VERSION 5.7 ;
  NOWIREEXTENSIONATPIN ON ;
  DIVIDERCHAR "/" ;
  BUSBITCHARS "[]" ;
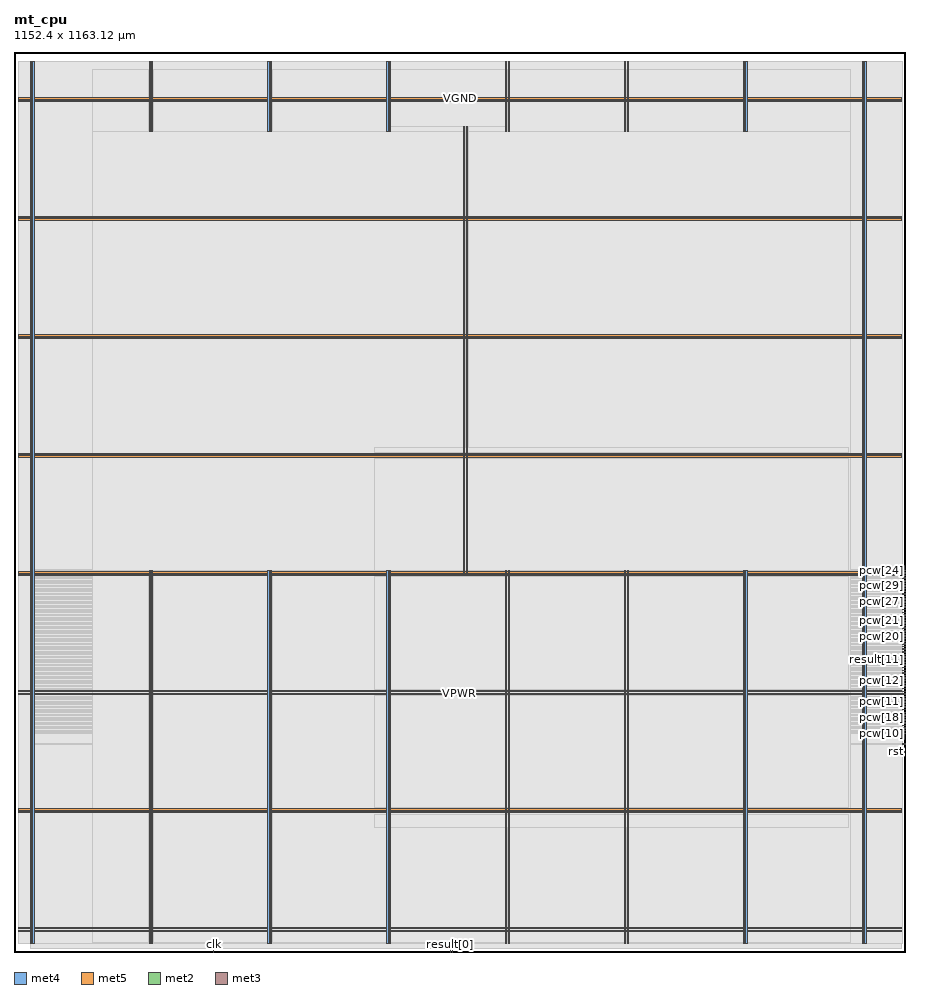
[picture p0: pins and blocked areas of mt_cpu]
MACRO mt_cpu
  CLASS BLOCK ;
  FOREIGN mt_cpu ;
  ORIGIN 0.000 0.000 ;
  SIZE 1152.405 BY 1163.125 ;
  PIN VGND
    DIRECTION INOUT ;
    USE GROUND ;
    PORT
      LAYER met4 ;
        RECT 24.340 10.640 25.940 1150.800 ;
    END
    PORT
      LAYER met4 ;
        RECT 177.940 10.640 179.540 492.595 ;
    END
    PORT
      LAYER met4 ;
        RECT 177.940 1060.925 179.540 1150.800 ;
    END
    PORT
      LAYER met4 ;
        RECT 331.540 10.640 333.140 492.595 ;
    END
    PORT
      LAYER met4 ;
        RECT 331.540 1060.925 333.140 1150.800 ;
    END
    PORT
      LAYER met4 ;
        RECT 485.140 10.640 486.740 492.595 ;
    END
    PORT
      LAYER met4 ;
        RECT 485.140 1060.925 486.740 1150.800 ;
    END
    PORT
      LAYER met4 ;
        RECT 638.740 10.640 640.340 492.595 ;
    END
    PORT
      LAYER met4 ;
        RECT 638.740 1060.925 640.340 1150.800 ;
    END
    PORT
      LAYER met4 ;
        RECT 792.340 10.640 793.940 492.595 ;
    END
    PORT
      LAYER met4 ;
        RECT 792.340 1060.925 793.940 1150.800 ;
    END
    PORT
      LAYER met4 ;
        RECT 945.940 10.640 947.540 492.595 ;
    END
    PORT
      LAYER met4 ;
        RECT 945.940 1060.925 947.540 1150.800 ;
    END
    PORT
      LAYER met4 ;
        RECT 1099.540 10.640 1101.140 1150.800 ;
    END
    PORT
      LAYER met5 ;
        RECT 5.280 30.030 1147.020 31.630 ;
    END
    PORT
      LAYER met5 ;
        RECT 5.280 183.210 1147.020 184.810 ;
    END
    PORT
      LAYER met5 ;
        RECT 5.280 336.390 1147.020 337.990 ;
    END
    PORT
      LAYER met5 ;
        RECT 5.280 489.570 1147.020 491.170 ;
    END
    PORT
      LAYER met5 ;
        RECT 5.280 642.750 1147.020 644.350 ;
    END
    PORT
      LAYER met5 ;
        RECT 5.280 795.930 1147.020 797.530 ;
    END
    PORT
      LAYER met5 ;
        RECT 5.280 949.110 1147.020 950.710 ;
    END
    PORT
      LAYER met5 ;
        RECT 5.280 1102.290 1147.020 1103.890 ;
    END
    PORT
      LAYER met4 ;
        RECT 584.780 486.640 586.380 1066.480 ;
    END
  END VGND
  PIN VPWR
    DIRECTION INOUT ;
    USE POWER ;
    PORT
      LAYER met4 ;
        RECT 21.040 10.640 22.640 1150.800 ;
    END
    PORT
      LAYER met4 ;
        RECT 174.640 10.640 176.240 492.595 ;
    END
    PORT
      LAYER met4 ;
        RECT 174.640 1060.925 176.240 1150.800 ;
    END
    PORT
      LAYER met4 ;
        RECT 328.240 10.640 329.840 492.595 ;
    END
    PORT
      LAYER met4 ;
        RECT 328.240 1060.925 329.840 1150.800 ;
    END
    PORT
      LAYER met4 ;
        RECT 481.840 10.640 483.440 492.595 ;
    END
    PORT
      LAYER met4 ;
        RECT 481.840 1060.925 483.440 1150.800 ;
    END
    PORT
      LAYER met4 ;
        RECT 635.440 10.640 637.040 492.595 ;
    END
    PORT
      LAYER met4 ;
        RECT 635.440 1060.925 637.040 1150.800 ;
    END
    PORT
      LAYER met4 ;
        RECT 789.040 10.640 790.640 492.595 ;
    END
    PORT
      LAYER met4 ;
        RECT 789.040 1060.925 790.640 1150.800 ;
    END
    PORT
      LAYER met4 ;
        RECT 942.640 10.640 944.240 492.595 ;
    END
    PORT
      LAYER met4 ;
        RECT 942.640 1060.925 944.240 1150.800 ;
    END
    PORT
      LAYER met4 ;
        RECT 1096.240 10.640 1097.840 1150.800 ;
    END
    PORT
      LAYER met5 ;
        RECT 5.280 26.730 1147.020 28.330 ;
    END
    PORT
      LAYER met5 ;
        RECT 5.280 179.910 1147.020 181.510 ;
    END
    PORT
      LAYER met5 ;
        RECT 5.280 333.090 1147.020 334.690 ;
    END
    PORT
      LAYER met5 ;
        RECT 5.280 486.270 1147.020 487.870 ;
    END
    PORT
      LAYER met5 ;
        RECT 5.280 639.450 1147.020 641.050 ;
    END
    PORT
      LAYER met5 ;
        RECT 5.280 792.630 1147.020 794.230 ;
    END
    PORT
      LAYER met5 ;
        RECT 5.280 945.810 1147.020 947.410 ;
    END
    PORT
      LAYER met5 ;
        RECT 5.280 1098.990 1147.020 1100.590 ;
    END
    PORT
      LAYER met4 ;
        RECT 581.100 486.640 582.700 1066.480 ;
    END
  END VPWR
  PIN clk
    DIRECTION INPUT ;
    USE SIGNAL ;
    ANTENNAGATEAREA 2.573400 ;
    ANTENNADIFFAREA 0.869400 ;
    PORT
      LAYER met2 ;
        RECT 257.690 0.000 257.970 4.000 ;
    END
  END clk
  PIN pcw[0]
    DIRECTION OUTPUT ;
    USE SIGNAL ;
    ANTENNADIFFAREA 0.340600 ;
    PORT
      LAYER met3 ;
        RECT 1148.405 387.640 1152.405 388.240 ;
    END
  END pcw[0]
  PIN pcw[10]
    DIRECTION OUTPUT ;
    USE SIGNAL ;
    ANTENNADIFFAREA 0.340600 ;
    PORT
      LAYER met3 ;
        RECT 1148.405 282.240 1152.405 282.840 ;
    END
  END pcw[10]
  PIN pcw[11]
    DIRECTION OUTPUT ;
    USE SIGNAL ;
    ANTENNADIFFAREA 0.340600 ;
    PORT
      LAYER met3 ;
        RECT 1148.405 323.040 1152.405 323.640 ;
    END
  END pcw[11]
  PIN pcw[12]
    DIRECTION OUTPUT ;
    USE SIGNAL ;
    ANTENNADIFFAREA 0.340600 ;
    PORT
      LAYER met3 ;
        RECT 1148.405 340.040 1152.405 340.640 ;
    END
  END pcw[12]
  PIN pcw[13]
    DIRECTION OUTPUT ;
    USE SIGNAL ;
    ANTENNADIFFAREA 0.340600 ;
    PORT
      LAYER met3 ;
        RECT 1148.405 326.440 1152.405 327.040 ;
    END
  END pcw[13]
  PIN pcw[14]
    DIRECTION OUTPUT ;
    USE SIGNAL ;
    ANTENNADIFFAREA 0.340600 ;
    PORT
      LAYER met3 ;
        RECT 1148.405 329.840 1152.405 330.440 ;
    END
  END pcw[14]
  PIN pcw[15]
    DIRECTION OUTPUT ;
    USE SIGNAL ;
    ANTENNADIFFAREA 0.340600 ;
    PORT
      LAYER met3 ;
        RECT 1148.405 333.240 1152.405 333.840 ;
    END
  END pcw[15]
  PIN pcw[16]
    DIRECTION OUTPUT ;
    USE SIGNAL ;
    ANTENNADIFFAREA 0.340600 ;
    PORT
      LAYER met3 ;
        RECT 1148.405 336.640 1152.405 337.240 ;
    END
  END pcw[16]
  PIN pcw[17]
    DIRECTION OUTPUT ;
    USE SIGNAL ;
    ANTENNADIFFAREA 0.340600 ;
    PORT
      LAYER met3 ;
        RECT 1148.405 306.040 1152.405 306.640 ;
    END
  END pcw[17]
  PIN pcw[18]
    DIRECTION OUTPUT ;
    USE SIGNAL ;
    ANTENNADIFFAREA 0.340600 ;
    PORT
      LAYER met3 ;
        RECT 1148.405 292.440 1152.405 293.040 ;
    END
  END pcw[18]
  PIN pcw[19]
    DIRECTION OUTPUT ;
    USE SIGNAL ;
    ANTENNADIFFAREA 0.340600 ;
    PORT
      LAYER met3 ;
        RECT 1148.405 380.840 1152.405 381.440 ;
    END
  END pcw[19]
  PIN pcw[1]
    DIRECTION OUTPUT ;
    USE SIGNAL ;
    ANTENNADIFFAREA 0.340600 ;
    PORT
      LAYER met3 ;
        RECT 1148.405 397.840 1152.405 398.440 ;
    END
  END pcw[1]
  PIN pcw[20]
    DIRECTION OUTPUT ;
    USE SIGNAL ;
    ANTENNADIFFAREA 0.340600 ;
    PORT
      LAYER met3 ;
        RECT 1148.405 408.040 1152.405 408.640 ;
    END
  END pcw[20]
  PIN pcw[21]
    DIRECTION OUTPUT ;
    USE SIGNAL ;
    ANTENNADIFFAREA 0.340600 ;
    PORT
      LAYER met3 ;
        RECT 1148.405 418.240 1152.405 418.840 ;
    END
  END pcw[21]
  PIN pcw[22]
    DIRECTION OUTPUT ;
    USE SIGNAL ;
    ANTENNADIFFAREA 0.340600 ;
    PORT
      LAYER met3 ;
        RECT 1148.405 421.640 1152.405 422.240 ;
    END
  END pcw[22]
  PIN pcw[23]
    DIRECTION OUTPUT ;
    USE SIGNAL ;
    ANTENNADIFFAREA 0.340600 ;
    PORT
      LAYER met3 ;
        RECT 1148.405 428.440 1152.405 429.040 ;
    END
  END pcw[23]
  PIN pcw[24]
    DIRECTION OUTPUT ;
    USE SIGNAL ;
    ANTENNADIFFAREA 0.340600 ;
    PORT
      LAYER met3 ;
        RECT 1148.405 493.040 1152.405 493.640 ;
    END
  END pcw[24]
  PIN pcw[25]
    DIRECTION OUTPUT ;
    USE SIGNAL ;
    ANTENNADIFFAREA 0.340600 ;
    PORT
      LAYER met3 ;
        RECT 1148.405 489.640 1152.405 490.240 ;
    END
  END pcw[25]
  PIN pcw[26]
    DIRECTION OUTPUT ;
    USE SIGNAL ;
    ANTENNADIFFAREA 0.340600 ;
    PORT
      LAYER met3 ;
        RECT 1148.405 486.240 1152.405 486.840 ;
    END
  END pcw[26]
  PIN pcw[27]
    DIRECTION OUTPUT ;
    USE SIGNAL ;
    ANTENNADIFFAREA 0.340600 ;
    PORT
      LAYER met3 ;
        RECT 1148.405 442.040 1152.405 442.640 ;
    END
  END pcw[27]
  PIN pcw[28]
    DIRECTION OUTPUT ;
    USE SIGNAL ;
    ANTENNADIFFAREA 0.340600 ;
    PORT
      LAYER met3 ;
        RECT 1148.405 445.440 1152.405 446.040 ;
    END
  END pcw[28]
  PIN pcw[29]
    DIRECTION OUTPUT ;
    USE SIGNAL ;
    ANTENNADIFFAREA 0.340600 ;
    PORT
      LAYER met3 ;
        RECT 1148.405 482.840 1152.405 483.440 ;
    END
  END pcw[29]
  PIN pcw[2]
    DIRECTION OUTPUT ;
    USE SIGNAL ;
    ANTENNADIFFAREA 0.340600 ;
    PORT
      LAYER met2 ;
        RECT 566.810 0.000 567.090 4.000 ;
    END
  END pcw[2]
  PIN pcw[30]
    DIRECTION OUTPUT ;
    USE SIGNAL ;
    ANTENNADIFFAREA 0.340600 ;
    PORT
      LAYER met3 ;
        RECT 1148.405 459.040 1152.405 459.640 ;
    END
  END pcw[30]
  PIN pcw[31]
    DIRECTION OUTPUT ;
    USE SIGNAL ;
    ANTENNADIFFAREA 0.340600 ;
    PORT
      LAYER met3 ;
        RECT 1148.405 452.240 1152.405 452.840 ;
    END
  END pcw[31]
  PIN pcw[3]
    DIRECTION OUTPUT ;
    USE SIGNAL ;
    ANTENNADIFFAREA 0.340600 ;
    PORT
      LAYER met3 ;
        RECT 1148.405 285.640 1152.405 286.240 ;
    END
  END pcw[3]
  PIN pcw[4]
    DIRECTION OUTPUT ;
    USE SIGNAL ;
    ANTENNADIFFAREA 0.340600 ;
    PORT
      LAYER met3 ;
        RECT 1148.405 360.440 1152.405 361.040 ;
    END
  END pcw[4]
  PIN pcw[5]
    DIRECTION OUTPUT ;
    USE SIGNAL ;
    ANTENNADIFFAREA 0.340600 ;
    PORT
      LAYER met3 ;
        RECT 1148.405 295.840 1152.405 296.440 ;
    END
  END pcw[5]
  PIN pcw[6]
    DIRECTION OUTPUT ;
    USE SIGNAL ;
    ANTENNADIFFAREA 0.340600 ;
    PORT
      LAYER met3 ;
        RECT 1148.405 302.640 1152.405 303.240 ;
    END
  END pcw[6]
  PIN pcw[7]
    DIRECTION OUTPUT ;
    USE SIGNAL ;
    ANTENNADIFFAREA 0.340600 ;
    PORT
      LAYER met3 ;
        RECT 1148.405 350.240 1152.405 350.840 ;
    END
  END pcw[7]
  PIN pcw[8]
    DIRECTION OUTPUT ;
    USE SIGNAL ;
    ANTENNADIFFAREA 0.340600 ;
    PORT
      LAYER met3 ;
        RECT 1148.405 309.440 1152.405 310.040 ;
    END
  END pcw[8]
  PIN pcw[9]
    DIRECTION OUTPUT ;
    USE SIGNAL ;
    ANTENNADIFFAREA 0.340600 ;
    PORT
      LAYER met3 ;
        RECT 1148.405 319.640 1152.405 320.240 ;
    END
  END pcw[9]
  PIN result[0]
    DIRECTION OUTPUT ;
    USE SIGNAL ;
    ANTENNADIFFAREA 0.340600 ;
    PORT
      LAYER met2 ;
        RECT 563.590 0.000 563.870 4.000 ;
    END
  END result[0]
  PIN result[10]
    DIRECTION OUTPUT ;
    USE SIGNAL ;
    ANTENNADIFFAREA 0.340600 ;
    PORT
      LAYER met3 ;
        RECT 1148.405 377.440 1152.405 378.040 ;
    END
  END result[10]
  PIN result[11]
    DIRECTION OUTPUT ;
    USE SIGNAL ;
    ANTENNADIFFAREA 0.340600 ;
    PORT
      LAYER met3 ;
        RECT 1148.405 367.240 1152.405 367.840 ;
    END
  END result[11]
  PIN result[12]
    DIRECTION OUTPUT ;
    USE SIGNAL ;
    ANTENNADIFFAREA 0.340600 ;
    PORT
      LAYER met3 ;
        RECT 1148.405 357.040 1152.405 357.640 ;
    END
  END result[12]
  PIN result[13]
    DIRECTION OUTPUT ;
    USE SIGNAL ;
    ANTENNADIFFAREA 0.340600 ;
    PORT
      LAYER met3 ;
        RECT 1148.405 299.240 1152.405 299.840 ;
    END
  END result[13]
  PIN result[14]
    DIRECTION OUTPUT ;
    USE SIGNAL ;
    ANTENNADIFFAREA 0.340600 ;
    PORT
      LAYER met3 ;
        RECT 1148.405 312.840 1152.405 313.440 ;
    END
  END result[14]
  PIN result[15]
    DIRECTION OUTPUT ;
    USE SIGNAL ;
    ANTENNADIFFAREA 0.340600 ;
    PORT
      LAYER met3 ;
        RECT 1148.405 343.440 1152.405 344.040 ;
    END
  END result[15]
  PIN result[16]
    DIRECTION OUTPUT ;
    USE SIGNAL ;
    ANTENNADIFFAREA 0.340600 ;
    PORT
      LAYER met3 ;
        RECT 1148.405 346.840 1152.405 347.440 ;
    END
  END result[16]
  PIN result[17]
    DIRECTION OUTPUT ;
    USE SIGNAL ;
    ANTENNADIFFAREA 0.340600 ;
    PORT
      LAYER met3 ;
        RECT 1148.405 289.040 1152.405 289.640 ;
    END
  END result[17]
  PIN result[18]
    DIRECTION OUTPUT ;
    USE SIGNAL ;
    ANTENNADIFFAREA 0.340600 ;
    PORT
      LAYER met3 ;
        RECT 1148.405 370.640 1152.405 371.240 ;
    END
  END result[18]
  PIN result[19]
    DIRECTION OUTPUT ;
    USE SIGNAL ;
    ANTENNADIFFAREA 0.340600 ;
    PORT
      LAYER met3 ;
        RECT 1148.405 404.640 1152.405 405.240 ;
    END
  END result[19]
  PIN result[1]
    DIRECTION OUTPUT ;
    USE SIGNAL ;
    ANTENNADIFFAREA 0.340600 ;
    PORT
      LAYER met3 ;
        RECT 1148.405 401.240 1152.405 401.840 ;
    END
  END result[1]
  PIN result[20]
    DIRECTION OUTPUT ;
    USE SIGNAL ;
    ANTENNADIFFAREA 0.340600 ;
    PORT
      LAYER met3 ;
        RECT 1148.405 431.840 1152.405 432.440 ;
    END
  END result[20]
  PIN result[21]
    DIRECTION OUTPUT ;
    USE SIGNAL ;
    ANTENNADIFFAREA 0.340600 ;
    PORT
      LAYER met3 ;
        RECT 1148.405 462.440 1152.405 463.040 ;
    END
  END result[21]
  PIN result[22]
    DIRECTION OUTPUT ;
    USE SIGNAL ;
    ANTENNADIFFAREA 0.340600 ;
    PORT
      LAYER met3 ;
        RECT 1148.405 425.040 1152.405 425.640 ;
    END
  END result[22]
  PIN result[23]
    DIRECTION OUTPUT ;
    USE SIGNAL ;
    ANTENNADIFFAREA 0.340600 ;
    PORT
      LAYER met3 ;
        RECT 1148.405 448.840 1152.405 449.440 ;
    END
  END result[23]
  PIN result[24]
    DIRECTION OUTPUT ;
    USE SIGNAL ;
    ANTENNADIFFAREA 0.340600 ;
    PORT
      LAYER met3 ;
        RECT 1148.405 465.840 1152.405 466.440 ;
    END
  END result[24]
  PIN result[25]
    DIRECTION OUTPUT ;
    USE SIGNAL ;
    ANTENNADIFFAREA 0.340600 ;
    PORT
      LAYER met3 ;
        RECT 1148.405 438.640 1152.405 439.240 ;
    END
  END result[25]
  PIN result[26]
    DIRECTION OUTPUT ;
    USE SIGNAL ;
    ANTENNADIFFAREA 0.340600 ;
    PORT
      LAYER met3 ;
        RECT 1148.405 435.240 1152.405 435.840 ;
    END
  END result[26]
  PIN result[27]
    DIRECTION OUTPUT ;
    USE SIGNAL ;
    ANTENNADIFFAREA 0.340600 ;
    PORT
      LAYER met3 ;
        RECT 1148.405 479.440 1152.405 480.040 ;
    END
  END result[27]
  PIN result[28]
    DIRECTION OUTPUT ;
    USE SIGNAL ;
    ANTENNADIFFAREA 0.340600 ;
    PORT
      LAYER met3 ;
        RECT 1148.405 476.040 1152.405 476.640 ;
    END
  END result[28]
  PIN result[29]
    DIRECTION OUTPUT ;
    USE SIGNAL ;
    ANTENNADIFFAREA 0.340600 ;
    PORT
      LAYER met3 ;
        RECT 1148.405 455.640 1152.405 456.240 ;
    END
  END result[29]
  PIN result[2]
    DIRECTION OUTPUT ;
    USE SIGNAL ;
    ANTENNADIFFAREA 0.340600 ;
    PORT
      LAYER met3 ;
        RECT 1148.405 384.240 1152.405 384.840 ;
    END
  END result[2]
  PIN result[30]
    DIRECTION OUTPUT ;
    USE SIGNAL ;
    ANTENNADIFFAREA 0.340600 ;
    PORT
      LAYER met3 ;
        RECT 1148.405 469.240 1152.405 469.840 ;
    END
  END result[30]
  PIN result[31]
    DIRECTION OUTPUT ;
    USE SIGNAL ;
    ANTENNADIFFAREA 0.340600 ;
    PORT
      LAYER met3 ;
        RECT 1148.405 472.640 1152.405 473.240 ;
    END
  END result[31]
  PIN result[3]
    DIRECTION OUTPUT ;
    USE SIGNAL ;
    ANTENNADIFFAREA 0.340600 ;
    PORT
      LAYER met3 ;
        RECT 1148.405 414.840 1152.405 415.440 ;
    END
  END result[3]
  PIN result[4]
    DIRECTION OUTPUT ;
    USE SIGNAL ;
    ANTENNADIFFAREA 0.340600 ;
    PORT
      LAYER met3 ;
        RECT 1148.405 411.440 1152.405 412.040 ;
    END
  END result[4]
  PIN result[5]
    DIRECTION OUTPUT ;
    USE SIGNAL ;
    ANTENNADIFFAREA 0.340600 ;
    PORT
      LAYER met3 ;
        RECT 1148.405 374.040 1152.405 374.640 ;
    END
  END result[5]
  PIN result[6]
    DIRECTION OUTPUT ;
    USE SIGNAL ;
    ANTENNADIFFAREA 0.340600 ;
    PORT
      LAYER met3 ;
        RECT 1148.405 363.840 1152.405 364.440 ;
    END
  END result[6]
  PIN result[7]
    DIRECTION OUTPUT ;
    USE SIGNAL ;
    ANTENNADIFFAREA 0.340600 ;
    PORT
      LAYER met3 ;
        RECT 1148.405 394.440 1152.405 395.040 ;
    END
  END result[7]
  PIN result[8]
    DIRECTION OUTPUT ;
    USE SIGNAL ;
    ANTENNADIFFAREA 0.340600 ;
    PORT
      LAYER met3 ;
        RECT 1148.405 391.040 1152.405 391.640 ;
    END
  END result[8]
  PIN result[9]
    DIRECTION OUTPUT ;
    USE SIGNAL ;
    ANTENNADIFFAREA 0.340600 ;
    PORT
      LAYER met3 ;
        RECT 1148.405 353.640 1152.405 354.240 ;
    END
  END result[9]
  PIN rst
    DIRECTION INPUT ;
    USE SIGNAL ;
    ANTENNAGATEAREA 0.929700 ;
    ANTENNADIFFAREA 0.434700 ;
    PORT
      LAYER met3 ;
        RECT 1148.405 268.640 1152.405 269.240 ;
    END
  END rst
  PIN swap_tgrp
    DIRECTION INPUT ;
    USE SIGNAL ;
    ANTENNAGATEAREA 0.682200 ;
    ANTENNADIFFAREA 0.434700 ;
    PORT
      LAYER met3 ;
        RECT 1148.405 316.240 1152.405 316.840 ;
    END
  END swap_tgrp
  OBS
      LAYER nwell ;
        RECT 5.330 10.795 1146.970 1150.750 ;
      LAYER li1 ;
        RECT 5.520 10.795 1146.780 1150.645 ;
      LAYER met1 ;
        RECT 5.520 10.640 1147.170 1150.800 ;
      LAYER met2 ;
        RECT 21.070 4.280 1147.150 1150.745 ;
        RECT 21.070 4.000 257.410 4.280 ;
        RECT 258.250 4.000 563.310 4.280 ;
        RECT 564.150 4.000 566.530 4.280 ;
        RECT 567.370 4.000 1147.150 4.280 ;
      LAYER met3 ;
        RECT 21.050 494.040 1148.405 1150.725 ;
        RECT 21.050 492.640 1148.005 494.040 ;
        RECT 21.050 490.640 1148.405 492.640 ;
        RECT 21.050 489.240 1148.005 490.640 ;
        RECT 21.050 487.240 1148.405 489.240 ;
        RECT 21.050 485.840 1148.005 487.240 ;
        RECT 21.050 483.840 1148.405 485.840 ;
        RECT 21.050 482.440 1148.005 483.840 ;
        RECT 21.050 480.440 1148.405 482.440 ;
        RECT 21.050 479.040 1148.005 480.440 ;
        RECT 21.050 477.040 1148.405 479.040 ;
        RECT 21.050 475.640 1148.005 477.040 ;
        RECT 21.050 473.640 1148.405 475.640 ;
        RECT 21.050 472.240 1148.005 473.640 ;
        RECT 21.050 470.240 1148.405 472.240 ;
        RECT 21.050 468.840 1148.005 470.240 ;
        RECT 21.050 466.840 1148.405 468.840 ;
        RECT 21.050 465.440 1148.005 466.840 ;
        RECT 21.050 463.440 1148.405 465.440 ;
        RECT 21.050 462.040 1148.005 463.440 ;
        RECT 21.050 460.040 1148.405 462.040 ;
        RECT 21.050 458.640 1148.005 460.040 ;
        RECT 21.050 456.640 1148.405 458.640 ;
        RECT 21.050 455.240 1148.005 456.640 ;
        RECT 21.050 453.240 1148.405 455.240 ;
        RECT 21.050 451.840 1148.005 453.240 ;
        RECT 21.050 449.840 1148.405 451.840 ;
        RECT 21.050 448.440 1148.005 449.840 ;
        RECT 21.050 446.440 1148.405 448.440 ;
        RECT 21.050 445.040 1148.005 446.440 ;
        RECT 21.050 443.040 1148.405 445.040 ;
        RECT 21.050 441.640 1148.005 443.040 ;
        RECT 21.050 439.640 1148.405 441.640 ;
        RECT 21.050 438.240 1148.005 439.640 ;
        RECT 21.050 436.240 1148.405 438.240 ;
        RECT 21.050 434.840 1148.005 436.240 ;
        RECT 21.050 432.840 1148.405 434.840 ;
        RECT 21.050 431.440 1148.005 432.840 ;
        RECT 21.050 429.440 1148.405 431.440 ;
        RECT 21.050 428.040 1148.005 429.440 ;
        RECT 21.050 426.040 1148.405 428.040 ;
        RECT 21.050 424.640 1148.005 426.040 ;
        RECT 21.050 422.640 1148.405 424.640 ;
        RECT 21.050 421.240 1148.005 422.640 ;
        RECT 21.050 419.240 1148.405 421.240 ;
        RECT 21.050 417.840 1148.005 419.240 ;
        RECT 21.050 415.840 1148.405 417.840 ;
        RECT 21.050 414.440 1148.005 415.840 ;
        RECT 21.050 412.440 1148.405 414.440 ;
        RECT 21.050 411.040 1148.005 412.440 ;
        RECT 21.050 409.040 1148.405 411.040 ;
        RECT 21.050 407.640 1148.005 409.040 ;
        RECT 21.050 405.640 1148.405 407.640 ;
        RECT 21.050 404.240 1148.005 405.640 ;
        RECT 21.050 402.240 1148.405 404.240 ;
        RECT 21.050 400.840 1148.005 402.240 ;
        RECT 21.050 398.840 1148.405 400.840 ;
        RECT 21.050 397.440 1148.005 398.840 ;
        RECT 21.050 395.440 1148.405 397.440 ;
        RECT 21.050 394.040 1148.005 395.440 ;
        RECT 21.050 392.040 1148.405 394.040 ;
        RECT 21.050 390.640 1148.005 392.040 ;
        RECT 21.050 388.640 1148.405 390.640 ;
        RECT 21.050 387.240 1148.005 388.640 ;
        RECT 21.050 385.240 1148.405 387.240 ;
        RECT 21.050 383.840 1148.005 385.240 ;
        RECT 21.050 381.840 1148.405 383.840 ;
        RECT 21.050 380.440 1148.005 381.840 ;
        RECT 21.050 378.440 1148.405 380.440 ;
        RECT 21.050 377.040 1148.005 378.440 ;
        RECT 21.050 375.040 1148.405 377.040 ;
        RECT 21.050 373.640 1148.005 375.040 ;
        RECT 21.050 371.640 1148.405 373.640 ;
        RECT 21.050 370.240 1148.005 371.640 ;
        RECT 21.050 368.240 1148.405 370.240 ;
        RECT 21.050 366.840 1148.005 368.240 ;
        RECT 21.050 364.840 1148.405 366.840 ;
        RECT 21.050 363.440 1148.005 364.840 ;
        RECT 21.050 361.440 1148.405 363.440 ;
        RECT 21.050 360.040 1148.005 361.440 ;
        RECT 21.050 358.040 1148.405 360.040 ;
        RECT 21.050 356.640 1148.005 358.040 ;
        RECT 21.050 354.640 1148.405 356.640 ;
        RECT 21.050 353.240 1148.005 354.640 ;
        RECT 21.050 351.240 1148.405 353.240 ;
        RECT 21.050 349.840 1148.005 351.240 ;
        RECT 21.050 347.840 1148.405 349.840 ;
        RECT 21.050 346.440 1148.005 347.840 ;
        RECT 21.050 344.440 1148.405 346.440 ;
        RECT 21.050 343.040 1148.005 344.440 ;
        RECT 21.050 341.040 1148.405 343.040 ;
        RECT 21.050 339.640 1148.005 341.040 ;
        RECT 21.050 337.640 1148.405 339.640 ;
        RECT 21.050 336.240 1148.005 337.640 ;
        RECT 21.050 334.240 1148.405 336.240 ;
        RECT 21.050 332.840 1148.005 334.240 ;
        RECT 21.050 330.840 1148.405 332.840 ;
        RECT 21.050 329.440 1148.005 330.840 ;
        RECT 21.050 327.440 1148.405 329.440 ;
        RECT 21.050 326.040 1148.005 327.440 ;
        RECT 21.050 324.040 1148.405 326.040 ;
        RECT 21.050 322.640 1148.005 324.040 ;
        RECT 21.050 320.640 1148.405 322.640 ;
        RECT 21.050 319.240 1148.005 320.640 ;
        RECT 21.050 317.240 1148.405 319.240 ;
        RECT 21.050 315.840 1148.005 317.240 ;
        RECT 21.050 313.840 1148.405 315.840 ;
        RECT 21.050 312.440 1148.005 313.840 ;
        RECT 21.050 310.440 1148.405 312.440 ;
        RECT 21.050 309.040 1148.005 310.440 ;
        RECT 21.050 307.040 1148.405 309.040 ;
        RECT 21.050 305.640 1148.005 307.040 ;
        RECT 21.050 303.640 1148.405 305.640 ;
        RECT 21.050 302.240 1148.005 303.640 ;
        RECT 21.050 300.240 1148.405 302.240 ;
        RECT 21.050 298.840 1148.005 300.240 ;
        RECT 21.050 296.840 1148.405 298.840 ;
        RECT 21.050 295.440 1148.005 296.840 ;
        RECT 21.050 293.440 1148.405 295.440 ;
        RECT 21.050 292.040 1148.005 293.440 ;
        RECT 21.050 290.040 1148.405 292.040 ;
        RECT 21.050 288.640 1148.005 290.040 ;
        RECT 21.050 286.640 1148.405 288.640 ;
        RECT 21.050 285.240 1148.005 286.640 ;
        RECT 21.050 283.240 1148.405 285.240 ;
        RECT 21.050 281.840 1148.005 283.240 ;
        RECT 21.050 269.640 1148.405 281.840 ;
        RECT 21.050 268.240 1148.005 269.640 ;
        RECT 21.050 10.715 1148.405 268.240 ;
      LAYER met4 ;
        RECT 101.495 1060.525 174.240 1140.865 ;
        RECT 176.640 1060.525 177.540 1140.865 ;
        RECT 179.940 1060.525 327.840 1140.865 ;
        RECT 330.240 1060.525 331.140 1140.865 ;
        RECT 333.540 1060.525 481.440 1140.865 ;
        RECT 483.840 1060.525 484.740 1140.865 ;
        RECT 487.140 1066.880 635.040 1140.865 ;
        RECT 487.140 1060.525 580.700 1066.880 ;
        RECT 101.495 492.995 580.700 1060.525 ;
        RECT 101.495 12.415 174.240 492.995 ;
        RECT 176.640 12.415 177.540 492.995 ;
        RECT 179.940 12.415 327.840 492.995 ;
        RECT 330.240 12.415 331.140 492.995 ;
        RECT 333.540 12.415 481.440 492.995 ;
        RECT 483.840 12.415 484.740 492.995 ;
        RECT 487.140 486.240 580.700 492.995 ;
        RECT 583.100 486.240 584.380 1066.880 ;
        RECT 586.780 1060.525 635.040 1066.880 ;
        RECT 637.440 1060.525 638.340 1140.865 ;
        RECT 640.740 1060.525 788.640 1140.865 ;
        RECT 791.040 1060.525 791.940 1140.865 ;
        RECT 794.340 1060.525 942.240 1140.865 ;
        RECT 944.640 1060.525 945.540 1140.865 ;
        RECT 947.940 1060.525 1081.625 1140.865 ;
        RECT 586.780 492.995 1081.625 1060.525 ;
        RECT 586.780 486.240 635.040 492.995 ;
        RECT 487.140 12.415 635.040 486.240 ;
        RECT 637.440 12.415 638.340 492.995 ;
        RECT 640.740 12.415 788.640 492.995 ;
        RECT 791.040 12.415 791.940 492.995 ;
        RECT 794.340 12.415 942.240 492.995 ;
        RECT 944.640 12.415 945.540 492.995 ;
        RECT 947.940 12.415 1081.625 492.995 ;
      LAYER met5 ;
        RECT 466.100 645.950 1078.580 651.900 ;
        RECT 466.100 492.770 1078.580 637.850 ;
        RECT 466.100 339.590 1078.580 484.670 ;
        RECT 466.100 186.410 1078.580 331.490 ;
        RECT 466.100 160.700 1078.580 178.310 ;
  END
END mt_cpu
END LIBRARY

